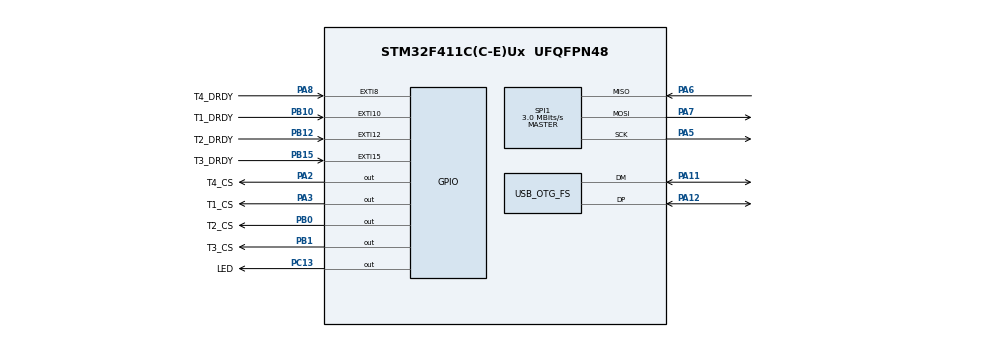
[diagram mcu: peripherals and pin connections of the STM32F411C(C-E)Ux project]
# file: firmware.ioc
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Mcu.Family=STM32F4
Mcu.Name=STM32F411C(C-E)Ux
Mcu.Package=UFQFPN48
NVIC.OTG_FS_IRQn=true\:0\:0\:false\:false\:true\:false\:true\:true
NVIC.PriorityGroup=NVIC_PRIORITYGROUP_4
PA11.Mode=Device_Only
PA11.Signal=USB_OTG_FS_DM
PA12.Mode=Device_Only
PA12.Signal=USB_OTG_FS_DP
PB10.GPIO_Label=T1_DRDY
PB10.GPIO_PuPd=GPIO_PULLUP
PB10.Signal=GPXTI10
PB10.GPIO_ModeDefaultEXTI=GPIO_MODE_IT_FALLING
PA3.GPIO_Label=T1_CS
PA3.GPIO_PuPd=GPIO_PULLUP
PA3.GPIO_Speed=GPIO_SPEED_FREQ_HIGH
PA3.PinState=GPIO_PIN_SET
PA3.Signal=GPIO_Output
PA5.GPIO_PuPd=GPIO_NOPULL
PA5.Mode=Full_Duplex_Master
PA5.Signal=SPI1_SCK
PA6.Mode=Full_Duplex_Master
PA6.Signal=SPI1_MISO
PA7.Mode=Full_Duplex_Master
PA7.Signal=SPI1_MOSI
PC13-ANTI_TAMP.GPIO_Label=LED
PC13-ANTI_TAMP.Signal=GPIO_Output
PH0\ -\ OSC_IN.Mode=HSE-External-Oscillator
PH0\ -\ OSC_IN.Signal=RCC_OSC_IN
PH1\ -\ OSC_OUT.Mode=HSE-External-Oscillator
PH1\ -\ OSC_OUT.Signal=RCC_OSC_OUT
ProjectManager.HeapSize=0x200
ProjectManager.StackSize=0x1000
ProjectManager.TargetToolchain=STM32CubeIDE
RCC.48MHZClocksFreq_Value=48000000
RCC.AHBFreq_Value=96000000
RCC.APB1CLKDivider=RCC_HCLK_DIV2
RCC.APB1Freq_Value=48000000
RCC.APB1TimFreq_Value=96000000
RCC.APB2CLKDivider=RCC_HCLK_DIV2
RCC.APB2Freq_Value=48000000
RCC.APB2TimFreq_Value=96000000
RCC.CortexFreq_Value=96000000
RCC.HCLKFreq_Value=96000000
RCC.HSE_VALUE=25000000
RCC.HSI_VALUE=16000000
RCC.LSE_VALUE=32768
RCC.PLLM=25
RCC.SYSCLKFreq_VALUE=96000000
RCC.SYSCLKSource=RCC_SYSCLKSOURCE_PLLCLK
RCC.VCOOutputFreq_Value=192000000
SPI1.BaudRatePrescaler=SPI_BAUDRATEPRESCALER_16
SPI1.CLKPhase=SPI_PHASE_2EDGE
SPI1.CLKPolarity=SPI_POLARITY_HIGH
SPI1.CalculateBaudRate=3.0 MBits/s
SPI1.Direction=SPI_DIRECTION_2LINES
SPI1.Mode=SPI_MODE_MASTER
SPI1.VirtualType=VM_MASTER
USB_DEVICE.CLASS_NAME_FS=CDC
USB_DEVICE.VirtualMode=Cdc
USB_DEVICE.VirtualModeFS=Cdc_FS
USB_OTG_FS.VirtualMode=Device_Only
VP_USB_DEVICE_VS_USB_DEVICE_CDC_FS.Mode=CDC_FS
board=custom
PB0.GPIO_Label=T2_CS
PB0.GPIO_PuPd=GPIO_PULLUP
PB0.GPIO_Speed=GPIO_SPEED_FREQ_HIGH
PB0.PinState=GPIO_PIN_SET
PB0.Signal=GPIO_Output
PB12.GPIO_Label=T2_DRDY
PB12.GPIO_PuPd=GPIO_PULLUP
PB12.Signal=GPXTI12
PB12.GPIO_ModeDefaultEXTI=GPIO_MODE_IT_FALLING
PB1.GPIO_Label=T3_CS
PB1.GPIO_PuPd=GPIO_PULLUP
PB1.GPIO_Speed=GPIO_SPEED_FREQ_HIGH
PB1.PinState=GPIO_PIN_SET
PB1.Signal=GPIO_Output
PB15.GPIO_Label=T3_DRDY
PB15.GPIO_PuPd=GPIO_PULLUP
PB15.Signal=GPXTI15
PB15.GPIO_ModeDefaultEXTI=GPIO_MODE_IT_FALLING
PA2.GPIO_Label=T4_CS
PA2.GPIO_PuPd=GPIO_PULLUP
PA2.GPIO_Speed=GPIO_SPEED_FREQ_HIGH
PA2.PinState=GPIO_PIN_SET
PA2.Signal=GPIO_Output
PA8.GPIO_Label=T4_DRDY
PA8.GPIO_PuPd=GPIO_PULLUP
PA8.Signal=GPXTI8
PA8.GPIO_ModeDefaultEXTI=GPIO_MODE_IT_FALLING
NVIC.EXTI15_10_IRQn=true\:6\:0\:false\:false\:true\:true\:true\:true
NVIC.EXTI9_5_IRQn=true\:6\:0\:false\:false\:true\:true\:true\:true

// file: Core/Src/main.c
/* USER CODE BEGIN Header */
/**
  ******************************************************************************
  * @file           : main.c
  * @brief          : Main program body
  ******************************************************************************
  * @attention
  *
  * Copyright (c) 2026 STMicroelectronics.
  * All rights reserved.
  *
  * This software is licensed under terms that can be found in the LICENSE file
  * in the root directory of this software component.
  * If no LICENSE file comes with this software, it is provided AS-IS.
  *
  ******************************************************************************
  */
/* USER CODE END Header */
#include "main.h"
#include "usb_device.h"

/* USER CODE BEGIN Includes */
#include "device_stm32.h"
#include "device_board_stm32.h"
/* USER CODE END Includes */

SPI_HandleTypeDef hspi1;

void SystemClock_Config(void);
static void MX_GPIO_Init(void);
static void MX_SPI1_Init(void);

int main(void)
{

  /* MCU Configuration--------------------------------------------------------*/

  /* Reset of all peripherals, Initializes the Flash interface and the Systick. */
  HAL_Init();

  /* Configure the system clock */
  SystemClock_Config();

  /* USER CODE BEGIN SysInit */
  device_board_gpio_init();

  /* USER CODE END SysInit */

  /* Initialize all configured peripherals */
  MX_GPIO_Init();
  MX_SPI1_Init();
  MX_USB_DEVICE_Init();
  /* USER CODE BEGIN 2 */
  device_app_init(&hspi1);
  /* USER CODE END 2 */

  /* Infinite loop */
  /* USER CODE BEGIN WHILE */
  while (1)
  {
    device_app_poll();
    /* USER CODE END WHILE */

  }
}

void SystemClock_Config(void)
{
  RCC_OscInitTypeDef RCC_OscInitStruct = {0};
  RCC_ClkInitTypeDef RCC_ClkInitStruct = {0};

  /** Configure the main internal regulator output voltage
  */
  __HAL_RCC_PWR_CLK_ENABLE();
  __HAL_PWR_VOLTAGESCALING_CONFIG(PWR_REGULATOR_VOLTAGE_SCALE1);

  /** Initializes the RCC Oscillators according to the specified parameters
  * in the RCC_OscInitTypeDef structure.
  */
  RCC_OscInitStruct.OscillatorType = RCC_OSCILLATORTYPE_HSE;
  RCC_OscInitStruct.HSEState = RCC_HSE_ON;
  RCC_OscInitStruct.PLL.PLLState = RCC_PLL_ON;
  RCC_OscInitStruct.PLL.PLLSource = RCC_PLLSOURCE_HSE;
  RCC_OscInitStruct.PLL.PLLM = DEVICE_PLL_M;
  RCC_OscInitStruct.PLL.PLLN = DEVICE_PLL_N;
  RCC_OscInitStruct.PLL.PLLP = RCC_PLLP_DIV2;
  RCC_OscInitStruct.PLL.PLLQ = DEVICE_PLL_Q;
  if (HAL_RCC_OscConfig(&RCC_OscInitStruct) != HAL_OK)
  {
    Error_Handler();
  }

  /** Initializes the CPU, AHB and APB buses clocks
  */
  RCC_ClkInitStruct.ClockType = RCC_CLOCKTYPE_HCLK|RCC_CLOCKTYPE_SYSCLK
                              |RCC_CLOCKTYPE_PCLK1|RCC_CLOCKTYPE_PCLK2;
  RCC_ClkInitStruct.SYSCLKSource = RCC_SYSCLKSOURCE_PLLCLK;
  RCC_ClkInitStruct.AHBCLKDivider = RCC_SYSCLK_DIV1;
  RCC_ClkInitStruct.APB1CLKDivider = DEVICE_APB1_DIV;
  RCC_ClkInitStruct.APB2CLKDivider = RCC_HCLK_DIV2;

  if (HAL_RCC_ClockConfig(&RCC_ClkInitStruct, FLASH_LATENCY_5) != HAL_OK)
  {
    Error_Handler();
  }
}

static void MX_SPI1_Init(void)
{

  /* SPI1 parameter configuration*/
  hspi1.Instance = DEVICE_SPI_INSTANCE;
  hspi1.Init.Mode = SPI_MODE_MASTER;
  hspi1.Init.Direction = SPI_DIRECTION_2LINES;
  hspi1.Init.DataSize = SPI_DATASIZE_8BIT;
  hspi1.Init.CLKPolarity = SPI_POLARITY_HIGH;
  hspi1.Init.CLKPhase = SPI_PHASE_2EDGE;
  hspi1.Init.NSS = SPI_NSS_SOFT;
  hspi1.Init.BaudRatePrescaler = DEVICE_SPI_PRESCALER;
  hspi1.Init.FirstBit = SPI_FIRSTBIT_MSB;
  hspi1.Init.TIMode = SPI_TIMODE_DISABLE;
  hspi1.Init.CRCCalculation = SPI_CRCCALCULATION_DISABLE;
  hspi1.Init.CRCPolynomial = 10;
  if (HAL_SPI_Init(&hspi1) != HAL_OK)
  {
    Error_Handler();
  }

}

static void MX_GPIO_Init(void)
{
  GPIO_InitTypeDef gpio = {0};
  /* Sensor and SPI pins are owned by device_board.h. */
  __HAL_RCC_GPIOC_CLK_ENABLE();
  HAL_GPIO_WritePin(LED_GPIO_Port, LED_Pin, GPIO_PIN_RESET);
  gpio.Pin = LED_Pin;
  gpio.Mode = GPIO_MODE_OUTPUT_PP;
  gpio.Pull = GPIO_NOPULL;
  gpio.Speed = GPIO_SPEED_FREQ_LOW;
  HAL_GPIO_Init(LED_GPIO_Port, &gpio);
}

void Error_Handler(void)
{
  __disable_irq();
  while (1)
  {
  }
}
